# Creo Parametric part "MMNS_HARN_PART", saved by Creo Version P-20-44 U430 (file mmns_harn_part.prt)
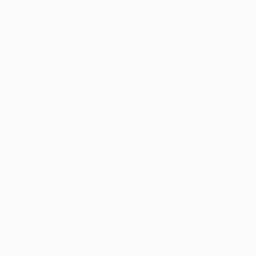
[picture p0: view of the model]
Units: millimeter Newton Second (mmNs); MM, TONNE, SECS

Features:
  1. coordinate system
  2. datum plane "RIGHT"
  3. datum plane "TOP"
  4. datum plane "FRONT"

Surfaces: 3 plane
